VERSION 5.8 ;
BUSBITCHARS "[]" ;
DIVIDERCHAR "/" ;
UNITS
    DATABASE MICRONS 1000 ;
END UNITS

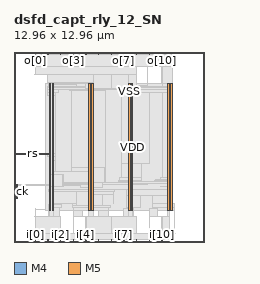
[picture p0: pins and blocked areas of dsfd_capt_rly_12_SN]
MACRO dsfd_capt_rly_12_SN
  FOREIGN dsfd_capt_rly_12_SN 0 0 ;
  CLASS BLOCK ;
  SIZE 12.96 BY 12.96 ;
  PIN ck
    DIRECTION INPUT ;
    USE SIGNAL ;
    PORT
      LAYER M4 ;
        RECT  0 2.976 0.192 3 ;
    END
    PORT
      LAYER M4 ;
        RECT  0.156 2.976 0.181 3 ;
    END
    PORT
      LAYER M4 ;
        RECT  0.181 2.976 0.227 3.912 ;
    END
  END ck
  PIN i[0]
    DIRECTION INPUT ;
    USE SIGNAL ;
    PORT
      LAYER M5 ;
        RECT  1.44 0 1.464 0.192 ;
    END
  END i[0]
  PIN i[10]
    DIRECTION INPUT ;
    USE SIGNAL ;
    PORT
      LAYER M5 ;
        RECT  10.08 0 10.104 0.192 ;
    END
  END i[10]
  PIN i[11]
    DIRECTION INPUT ;
    USE SIGNAL ;
    PORT
      LAYER M5 ;
        RECT  10.944 0 10.968 0.192 ;
    END
  END i[11]
  PIN i[1]
    DIRECTION INPUT ;
    USE SIGNAL ;
    PORT
      LAYER M5 ;
        RECT  2.304 0 2.328 0.192 ;
    END
  END i[1]
  PIN i[2]
    DIRECTION INPUT ;
    USE SIGNAL ;
    PORT
      LAYER M5 ;
        RECT  3.168 0 3.192 0.192 ;
    END
  END i[2]
  PIN i[3]
    DIRECTION INPUT ;
    USE SIGNAL ;
    PORT
      LAYER M5 ;
        RECT  4.032 0 4.056 0.192 ;
    END
  END i[3]
  PIN i[4]
    DIRECTION INPUT ;
    USE SIGNAL ;
    PORT
      LAYER M5 ;
        RECT  4.896 0 4.92 0.192 ;
    END
  END i[4]
  PIN i[5]
    DIRECTION INPUT ;
    USE SIGNAL ;
    PORT
      LAYER M5 ;
        RECT  5.76 0 5.784 0.192 ;
    END
  END i[5]
  PIN i[6]
    DIRECTION INPUT ;
    USE SIGNAL ;
    PORT
      LAYER M5 ;
        RECT  6.624 0 6.648 0.192 ;
    END
  END i[6]
  PIN i[7]
    DIRECTION INPUT ;
    USE SIGNAL ;
    PORT
      LAYER M5 ;
        RECT  7.488 0 7.512 0.192 ;
    END
  END i[7]
  PIN i[8]
    DIRECTION INPUT ;
    USE SIGNAL ;
    PORT
      LAYER M5 ;
        RECT  8.352 0 8.376 0.192 ;
    END
  END i[8]
  PIN i[9]
    DIRECTION INPUT ;
    USE SIGNAL ;
    PORT
      LAYER M5 ;
        RECT  9.216 0 9.24 0.192 ;
    END
  END i[9]
  PIN o[0]
    DIRECTION OUTPUT ;
    USE SIGNAL ;
    PORT
      LAYER M5 ;
        RECT  1.44 12.768 1.464 12.96 ;
    END
  END o[0]
  PIN o[10]
    DIRECTION OUTPUT ;
    USE SIGNAL ;
    PORT
      LAYER M5 ;
        RECT  10.08 12.768 10.104 12.96 ;
    END
  END o[10]
  PIN o[11]
    DIRECTION OUTPUT ;
    USE SIGNAL ;
    PORT
      LAYER M5 ;
        RECT  10.944 12.768 10.968 12.96 ;
    END
  END o[11]
  PIN o[1]
    DIRECTION OUTPUT ;
    USE SIGNAL ;
    PORT
      LAYER M5 ;
        RECT  2.304 12.768 2.328 12.96 ;
    END
  END o[1]
  PIN o[2]
    DIRECTION OUTPUT ;
    USE SIGNAL ;
    PORT
      LAYER M5 ;
        RECT  3.168 12.768 3.192 12.96 ;
    END
  END o[2]
  PIN o[3]
    DIRECTION OUTPUT ;
    USE SIGNAL ;
    PORT
      LAYER M5 ;
        RECT  4.032 12.768 4.056 12.96 ;
    END
  END o[3]
  PIN o[4]
    DIRECTION OUTPUT ;
    USE SIGNAL ;
    PORT
      LAYER M5 ;
        RECT  4.896 12.768 4.92 12.96 ;
    END
  END o[4]
  PIN o[5]
    DIRECTION OUTPUT ;
    USE SIGNAL ;
    PORT
      LAYER M5 ;
        RECT  5.76 12.768 5.784 12.96 ;
    END
  END o[5]
  PIN o[6]
    DIRECTION OUTPUT ;
    USE SIGNAL ;
    PORT
      LAYER M5 ;
        RECT  6.624 12.768 6.648 12.96 ;
    END
  END o[6]
  PIN o[7]
    DIRECTION OUTPUT ;
    USE SIGNAL ;
    PORT
      LAYER M5 ;
        RECT  7.488 12.768 7.512 12.96 ;
    END
  END o[7]
  PIN o[8]
    DIRECTION OUTPUT ;
    USE SIGNAL ;
    PORT
      LAYER M5 ;
        RECT  8.352 12.768 8.376 12.96 ;
    END
  END o[8]
  PIN o[9]
    DIRECTION OUTPUT ;
    USE SIGNAL ;
    PORT
      LAYER M5 ;
        RECT  9.216 12.768 9.24 12.96 ;
    END
  END o[9]
  PIN rs
    DIRECTION INPUT ;
    USE SIGNAL ;
    PORT
      LAYER M4 ;
        RECT  0 6 0.192 6.024 ;
    END
    PORT
      LAYER M4 ;
        RECT  0.156 6 2.408 6.024 ;
    END
  END rs
  PIN VDD
    DIRECTION INOUT ;
    USE POWER ;
    PORT
      LAYER M5 ;
        RECT  10.692 2.151 10.812 10.809 ;
        RECT  7.992 2.151 8.112 10.809 ;
        RECT  5.292 2.151 5.412 10.809 ;
        RECT  2.592 2.151 2.712 10.809 ;
    END
  END VDD
  PIN VSS
    DIRECTION INOUT ;
    USE GROUND ;
    PORT
      LAYER M5 ;
        RECT  10.5 2.137 10.62 10.823 ;
        RECT  7.8 2.137 7.92 10.823 ;
        RECT  5.1 2.137 5.22 10.823 ;
        RECT  2.4 2.137 2.52 10.823 ;
    END
  END VSS
  # OT_OBS_CLOSED layer=M5 d_um=1.536 added=12
  OBS
    LAYER RVTN ;
     RECT  2.16 2.16 10.8 2.295 ;
     RECT  2.16 2.565 10.8 2.835 ;
     RECT  2.16 3.105 10.8 3.375 ;
     RECT  2.16 3.645 10.8 3.915 ;
     RECT  2.16 4.185 10.8 4.455 ;
     RECT  2.16 4.725 10.8 4.995 ;
     RECT  2.16 5.265 10.8 5.535 ;
     RECT  2.16 5.805 10.8 6.075 ;
     RECT  2.16 6.345 10.8 6.615 ;
     RECT  2.16 6.885 10.8 7.155 ;
     RECT  2.16 7.425 10.8 7.695 ;
     RECT  2.16 7.965 10.8 8.235 ;
     RECT  2.16 8.505 10.8 8.775 ;
     RECT  2.16 9.045 10.8 9.315 ;
     RECT  2.16 9.585 10.8 9.855 ;
     RECT  2.16 10.125 10.8 10.395 ;
     RECT  2.16 10.665 10.8 10.8 ;
    LAYER RVTP ;
     RECT  2.16 2.295 10.8 2.565 ;
     RECT  2.16 2.835 10.8 3.105 ;
     RECT  2.16 3.375 10.8 3.645 ;
     RECT  2.16 3.915 10.8 4.185 ;
     RECT  2.16 4.455 10.8 4.725 ;
     RECT  2.16 4.995 10.8 5.265 ;
     RECT  2.16 5.535 10.8 5.805 ;
     RECT  2.16 6.075 10.8 6.345 ;
     RECT  2.16 6.615 10.8 6.885 ;
     RECT  2.16 7.155 10.8 7.425 ;
     RECT  2.16 7.695 10.8 7.965 ;
     RECT  2.16 8.235 10.8 8.505 ;
     RECT  2.16 8.775 10.8 9.045 ;
     RECT  2.16 9.315 10.8 9.585 ;
     RECT  2.16 9.855 10.8 10.125 ;
     RECT  2.16 10.395 10.8 10.665 ;
    LAYER M1 ;
     RECT  2.16 2.151 10.8 10.809 ;
    LAYER M2 ;
     RECT  1.471 2.232 2.16 2.25 ;
     RECT  2.16 2.151 10.8 10.809 ;
     RECT  10.8 2.421 10.812 10.539 ;
     RECT  10.812 2.61 10.967 2.628 ;
    LAYER M3 ;
     RECT  4.032 0.571 4.05 1.723 ;
     RECT  5.76 0.571 5.778 1.723 ;
     RECT  7.488 0.571 7.506 1.723 ;
     RECT  9.216 0.571 9.234 1.723 ;
     RECT  4.032 1.723 4.698 2.143 ;
     RECT  5.76 1.723 6.426 2.143 ;
     RECT  10.944 0.571 10.962 2.143 ;
     RECT  1.476 1.723 1.494 2.255 ;
     RECT  7.488 1.723 8.154 2.291 ;
     RECT  9.216 1.723 9.774 2.291 ;
     RECT  2.34 1.723 3.078 2.371 ;
     RECT  4.032 2.143 6.426 2.371 ;
     RECT  7.704 2.291 8.154 2.371 ;
     RECT  9.468 2.291 9.774 2.371 ;
     RECT  10.515 2.143 10.962 2.371 ;
     RECT  3.996 2.371 6.57 2.489 ;
     RECT  2.34 2.371 3.222 2.525 ;
     RECT  9.468 2.371 10.962 2.633 ;
     RECT  2.415 2.525 3.222 2.641 ;
     RECT  3.996 2.489 4.266 2.641 ;
     RECT  7.704 2.371 8.622 3.145 ;
     RECT  9.468 2.633 10.797 3.145 ;
     RECT  5.115 2.489 6.03 3.271 ;
     RECT  6.768 2.641 6.786 3.271 ;
     RECT  2.415 2.641 4.266 3.415 ;
     RECT  5.115 3.271 6.786 3.415 ;
     RECT  2.415 3.415 6.786 3.451 ;
     RECT  2.376 3.451 6.822 3.605 ;
     RECT  2.415 3.605 6.822 3.613 ;
     RECT  7.704 3.145 10.797 3.613 ;
     RECT  2.415 3.613 10.797 3.983 ;
     RECT  2.415 3.983 6.246 4.061 ;
     RECT  7.128 3.983 10.797 4.145 ;
     RECT  7.128 4.145 8.73 4.181 ;
     RECT  9.576 4.145 10.797 4.181 ;
     RECT  9.684 4.181 10.797 4.289 ;
     RECT  7.2 4.181 8.73 4.415 ;
     RECT  9.972 4.289 10.797 4.415 ;
     RECT  2.415 4.061 5.397 4.829 ;
     RECT  3.888 4.829 5.397 5.071 ;
     RECT  6.156 4.061 6.246 5.071 ;
     RECT  7.344 4.415 8.73 5.341 ;
     RECT  2.415 4.829 2.862 5.575 ;
     RECT  2.412 5.575 2.862 5.845 ;
     RECT  2.304 5.845 2.862 6.029 ;
     RECT  2.415 6.029 2.862 10.021 ;
     RECT  2.304 10.021 2.862 10.165 ;
     RECT  7.344 5.341 9.27 10.165 ;
     RECT  10.116 4.415 10.797 10.165 ;
     RECT  3.888 5.071 6.246 10.327 ;
     RECT  3.816 10.327 6.246 10.399 ;
     RECT  7.344 10.165 10.797 10.399 ;
     RECT  2.304 10.165 3.042 10.435 ;
     RECT  3.816 10.399 10.797 10.435 ;
     RECT  2.304 10.435 10.797 10.547 ;
     RECT  2.304 10.547 5.238 10.589 ;
     RECT  5.976 10.547 10.674 10.589 ;
     RECT  2.304 10.589 4.266 10.625 ;
     RECT  5.115 10.589 5.238 10.625 ;
     RECT  6.084 10.589 6.246 10.625 ;
     RECT  7.344 10.589 9.126 10.661 ;
     RECT  2.34 10.625 4.266 10.769 ;
     RECT  7.344 10.661 8.262 10.769 ;
     RECT  5.115 10.625 5.205 10.817 ;
     RECT  7.488 10.769 7.905 10.817 ;
     RECT  2.34 10.769 3.222 10.829 ;
     RECT  4.248 10.769 4.266 10.877 ;
     RECT  10.152 10.589 10.674 10.877 ;
     RECT  2.34 10.829 2.826 10.925 ;
     RECT  2.808 10.925 2.826 11.453 ;
     RECT  6.084 10.625 6.102 11.453 ;
     RECT  7.488 10.817 7.506 11.453 ;
     RECT  10.656 10.877 10.674 11.981 ;
     RECT  9.108 10.661 9.126 12.029 ;
    LAYER M4 ;
     RECT  1.429 11.424 2.293 11.448 ;
     RECT  1.421 1.728 2.408 1.752 ;
     RECT  0.227 3.888 2.408 3.912 ;
     RECT  2.293 10.896 2.408 11.448 ;
     RECT  2.408 1.728 2.704 11.448 ;
     RECT  2.704 10.8 2.837 11.448 ;
     RECT  2.704 1.728 3.203 1.752 ;
     RECT  2.837 10.8 3.233 10.824 ;
     RECT  2.704 3.792 3.347 4.584 ;
     RECT  3.347 3.888 3.377 4.584 ;
     RECT  4.021 0.576 4.105 0.6 ;
     RECT  4.021 10.848 4.277 10.872 ;
     RECT  3.377 3.888 4.561 3.912 ;
     RECT  4.669 1.728 4.931 1.752 ;
     RECT  4.561 3.696 5.108 3.912 ;
     RECT  4.885 10.512 5.108 10.812 ;
     RECT  5.108 2.148 5.212 10.812 ;
     RECT  5.212 2.418 5.404 10.812 ;
     RECT  5.749 0.576 5.833 0.6 ;
     RECT  5.404 3.696 6.005 4.056 ;
     RECT  5.749 11.424 6.113 11.448 ;
     RECT  6.397 1.728 6.659 1.752 ;
     RECT  6.613 10.512 6.833 10.536 ;
     RECT  7.436 11.424 7.523 11.448 ;
     RECT  7.477 0.576 7.561 0.6 ;
     RECT  6.005 3.936 7.808 4.056 ;
     RECT  7.808 2.148 7.912 10.812 ;
     RECT  7.912 2.148 8.104 10.542 ;
     RECT  8.125 1.728 8.387 1.752 ;
     RECT  8.104 10.272 8.561 10.296 ;
     RECT  8.104 3.936 9.137 3.96 ;
     RECT  9.097 12 9.251 12.024 ;
     RECT  9.205 0.576 9.289 0.6 ;
     RECT  9.745 1.728 10.115 1.752 ;
     RECT  10.069 10.848 10.181 10.872 ;
     RECT  9.961 3.792 10.508 3.816 ;
     RECT  10.508 2.148 10.612 10.812 ;
     RECT  10.612 2.418 10.804 10.542 ;
     RECT  10.645 11.952 10.979 11.976 ;
     RECT  10.933 0.576 11.017 0.6 ;
    LAYER M5 ;
     RECT  1.464 0.144 2.304 0.192 ;
     RECT  2.328 0.144 3.168 0.192 ;
     RECT  3.192 0.144 4.032 0.192 ;
     RECT  4.056 0.144 4.896 0.192 ;
     RECT  4.92 0.144 5.76 0.192 ;
     RECT  5.784 0.144 6.624 0.192 ;
     RECT  6.648 0.144 7.488 0.192 ;
     RECT  7.512 0.144 8.352 0.192 ;
     RECT  8.376 0.144 9.216 0.192 ;
     RECT  9.24 0.144 10.08 0.192 ;
     RECT  10.104 0.144 10.944 0.192 ;
     RECT  1.44 0.192 10.968 0.611 ;
     RECT  1.44 0.611 3.192 1.763 ;
     RECT  4.896 0.611 4.92 1.763 ;
     RECT  6.624 0.611 6.648 1.763 ;
     RECT  8.352 0.611 8.376 1.763 ;
     RECT  10.08 0.611 10.104 1.763 ;
     RECT  5.1 2.137 5.22 2.151 ;
     RECT  10.5 2.137 10.62 2.151 ;
     RECT  2.4 1.763 2.712 3.781 ;
     RECT  0.192 2.965 0.216 3.923 ;
     RECT  2.4 3.781 3.336 4.595 ;
     RECT  7.8 2.137 8.112 10.261 ;
     RECT  5.1 2.151 5.412 10.501 ;
     RECT  2.4 4.595 2.712 10.789 ;
     RECT  10.5 2.151 10.812 10.809 ;
     RECT  10.5 10.809 10.62 10.823 ;
     RECT  2.4 10.789 3.192 10.837 ;
     RECT  4.896 10.501 5.412 10.837 ;
     RECT  2.4 10.837 5.412 10.885 ;
     RECT  2.304 10.885 5.412 11.413 ;
     RECT  6.624 10.501 6.648 11.413 ;
     RECT  7.8 10.261 8.376 11.413 ;
     RECT  10.08 10.837 10.104 11.941 ;
     RECT  1.44 11.413 8.376 11.989 ;
     RECT  10.08 11.941 10.968 11.989 ;
     RECT  1.44 11.989 10.968 12.768 ;
     RECT  1.464 12.768 2.304 12.816 ;
     RECT  2.328 12.768 3.168 12.816 ;
     RECT  3.192 12.768 4.032 12.816 ;
     RECT  4.056 12.768 4.896 12.816 ;
     RECT  4.92 12.768 5.76 12.816 ;
     RECT  5.784 12.768 6.624 12.816 ;
     RECT  6.648 12.768 7.488 12.816 ;
     RECT  7.512 12.768 8.352 12.816 ;
     RECT  8.376 12.768 9.216 12.816 ;
     RECT  9.24 12.768 10.08 12.816 ;
     RECT  10.104 12.768 10.944 12.816 ;
     RECT  4.92 0.611 6.624 1.763 ;
     RECT  6.648 0.611 8.352 1.763 ;
     RECT  10.104 0.611 10.62 1.763 ;
     RECT  5.1 1.763 5.412 2.137 ;
     RECT  7.8 1.763 8.112 2.137 ;
     RECT  10.5 1.763 10.62 2.137 ;
     RECT  5.22 2.137 5.412 2.151 ;
     RECT  5.412 10.501 6.624 11.413 ;
     RECT  6.648 10.501 7.8 11.413 ;
     RECT  10.62 10.809 10.812 10.823 ;
     RECT  10.5 10.823 10.812 10.837 ;
     RECT  10.104 10.837 10.812 11.941 ;
  END
END dsfd_capt_rly_12_SN
END LIBRARY
